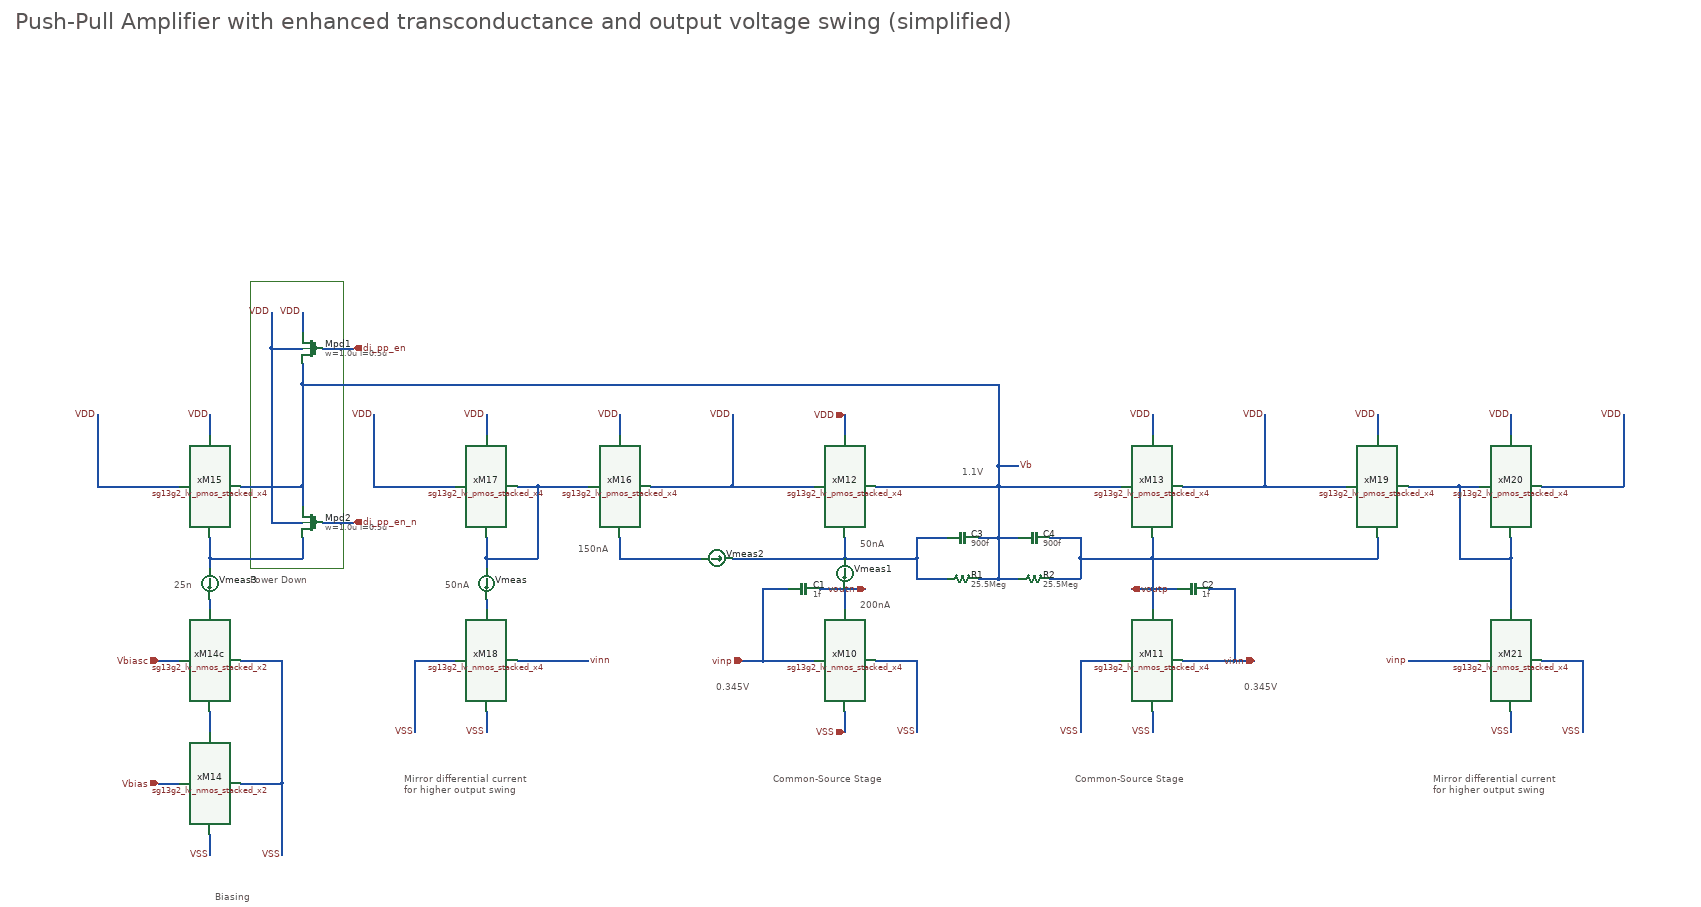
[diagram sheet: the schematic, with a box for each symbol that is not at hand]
v {xschem version=3.4.6 file_version=1.2}
G {}
K {}
V {}
S {}
E {}
P 4 5 640 -1280 640 -1840 820 -1840 820 -1280 640 -1280 {dash = 8}
T {Push-Pull Amplifier with enhanced transconductance and output voltage swing (simplified)} 180 -2360 0 0 1.3 1.3 {}
T {200nA} 1830 -1220 0 0 0.4 0.4 {}
T {Common-Source Stage} 1660 -880 0 0 0.5 0.5 {}
T {Common-Source Stage} 2250 -880 0 0 0.5 0.5 {}
T {Mirror differential current
for higher output swing} 940 -880 0 0 0.5 0.5 {}
T {Mirror differential current
for higher output swing} 2950 -880 0 0 0.5 0.5 {}
T {50nA} 1020 -1260 0 0 0.4 0.4 {}
T {150nA} 1280 -1330 0 0 0.4 0.4 {}
T {50nA} 1830 -1340 0 0 0.4 0.4 {}
T {25n} 490 -1260 0 0 0.4 0.4 {}
T {0.345V} 1550 -1060 0 0 0.4 0.4 {}
T {0.345V} 2580 -1060 0 0 0.4 0.4 {}
T {1.1V} 2030 -1480 0 0 0.4 0.4 {}
T {Power Down} 640 -1270 0 0 0.4 0.4 {}
T {Biasing} 570 -650 0 0 0.5 0.5 {}
N 1800 -1580 1800 -1540 {lab=VDD}
N 1940 -1100 1940 -960 {lab=VSS}
N 2560 -1100 2600 -1100 {lab=vinn}
N 2460 -1100 2560 -1100 {lab=vinn}
N 2260 -1100 2260 -960 {lab=VSS}
N 2400 -1240 2400 -1200 {lab=voutp}
N 1580 -1580 1580 -1440 {lab=VDD}
N 2620 -1580 2620 -1440 {lab=VDD}
N 1580 -1440 1740 -1440 {lab=VDD}
N 2460 -1440 2620 -1440 {lab=VDD}
N 1940 -1260 2000 -1260 {lab=#net1}
N 2200 -1260 2260 -1260 {lab=voutp}
N 2100 -1260 2140 -1260 {lab=Vb}
N 2060 -1260 2100 -1260 {lab=Vb}
N 2100 -1340 2100 -1260 {lab=Vb}
N 2200 -1340 2260 -1340 {lab=voutp}
N 2100 -1340 2140 -1340 {lab=Vb}
N 2060 -1340 2100 -1340 {lab=Vb}
N 1940 -1340 2000 -1340 {lab=#net1}
N 1860 -1440 2100 -1440 {lab=Vb}
N 2100 -1440 2340 -1440 {lab=Vb}
N 2400 -1300 2400 -1240 {lab=voutp}
N 340 -1580 340 -1440 {lab=VDD}
N 340 -1440 500 -1440 {lab=VDD}
N 560 -1580 560 -1540 {lab=VDD}
N 1940 -1300 1940 -1260 {lab=#net1}
N 1420 -1440 1580 -1440 {lab=VDD}
N 2400 -1340 2400 -1300 {lab=voutp}
N 1360 -1580 1360 -1540 {lab=VDD}
N 880 -1440 1040 -1440 {lab=VDD}
N 880 -1580 880 -1440 {lab=VDD}
N 1100 -1580 1100 -1540 {lab=VDD}
N 1160 -1100 1300 -1100 {lab=vinn}
N 1100 -1000 1100 -960 {lab=VSS}
N 1860 -1100 1940 -1100 {lab=VSS}
N 1800 -1000 1800 -960 {lab=VSS}
N 1640 -1100 1740 -1100 {lab=vinp}
N 2400 -1000 2400 -960 {lab=VSS}
N 2260 -1100 2340 -1100 {lab=VSS}
N 2560 -1240 2560 -1100 {lab=vinn}
N 2260 -1300 2260 -1260 {lab=voutp}
N 1360 -1340 1360 -1300 {lab=#net2}
N 1800 -1340 1800 -1300 {lab=#net1}
N 2510 -1240 2560 -1240 {lab=vinn}
N 2400 -1240 2450 -1240 {lab=voutp}
N 1750 -1240 1800 -1240 {lab=voutn}
N 1640 -1240 1690 -1240 {lab=vinp}
N 1640 -1240 1640 -1100 {lab=vinp}
N 1600 -1100 1640 -1100 {lab=vinp}
N 1800 -1240 1800 -1200 {lab=voutn}
N 1200 -1440 1300 -1440 {lab=#net3}
N 1100 -1300 1200 -1300 {lab=#net3}
N 1100 -1340 1100 -1300 {lab=#net3}
N 1200 -1440 1200 -1300 {lab=#net3}
N 1160 -1440 1200 -1440 {lab=#net3}
N 2840 -1580 2840 -1540 {lab=VDD}
N 3160 -1440 3320 -1440 {lab=VDD}
N 3320 -1580 3320 -1440 {lab=VDD}
N 3100 -1580 3100 -1540 {lab=VDD}
N 2900 -1100 3040 -1100 {lab=vinp}
N 3100 -1300 3100 -1200 {lab=#net4}
N 3160 -1100 3240 -1100 {lab=VSS}
N 3240 -1100 3240 -960 {lab=VSS}
N 3100 -1000 3100 -960 {lab=VSS}
N 2840 -1340 2840 -1300 {lab=voutp}
N 2900 -1440 3000 -1440 {lab=#net4}
N 3000 -1300 3100 -1300 {lab=#net4}
N 3100 -1340 3100 -1300 {lab=#net4}
N 3000 -1440 3000 -1300 {lab=#net4}
N 3000 -1440 3040 -1440 {lab=#net4}
N 2620 -1440 2780 -1440 {lab=VDD}
N 1100 -1300 1100 -1280 {lab=#net3}
N 1100 -1220 1100 -1200 {lab=#net5}
N 2400 -1300 2840 -1300 {lab=voutp}
N 2100 -1480 2100 -1440 {lab=Vb}
N 1800 -1300 1940 -1300 {lab=#net1}
N 1940 -1340 1940 -1300 {lab=#net1}
N 2260 -1300 2400 -1300 {lab=voutp}
N 2260 -1340 2260 -1300 {lab=voutp}
N 2100 -1440 2100 -1340 {lab=Vb}
N 2360 -1240 2400 -1240 {lab=voutp}
N 1800 -1240 1840 -1240 {lab=voutn}
N 1360 -1300 1520 -1300 {lab=#net2}
N 1580 -1300 1800 -1300 {lab=#net1}
N 2100 -1480 2140 -1480 {lab=Vb}
N 560 -1300 560 -1280 {lab=#net6}
N 960 -1100 960 -960 {lab=VSS}
N 2400 -1580 2400 -1540 {lab=VDD}
N 2100 -1640 2100 -1480 {lab=Vb}
N 740 -1640 740 -1440 {lab=Vb}
N 740 -1780 740 -1740 {lab=VDD}
N 740 -1440 740 -1400 {lab=Vb}
N 740 -1340 740 -1300 {lab=#net6}
N 560 -1300 740 -1300 {lab=#net6}
N 560 -1340 560 -1300 {lab=#net6}
N 620 -1440 740 -1440 {lab=Vb}
N 740 -1680 740 -1640 {lab=Vb}
N 740 -1640 2100 -1640 {lab=Vb}
N 680 -1710 680 -1370 {lab=VDD}
N 680 -1370 740 -1370 {lab=VDD}
N 680 -1710 740 -1710 {lab=VDD}
N 680 -1780 680 -1710 {lab=VDD}
N 960 -1100 1040 -1100 {lab=VSS}
N 780 -1370 840 -1370 {lab=di_pp_en_n}
N 780 -1710 840 -1710 {lab=di_pp_en}
N 560 -1220 560 -1200 {lab=#net3}
N 620 -1100 700 -1100 {lab=VSS}
N 700 -860 700 -720 {lab=VSS}
N 560 -1000 560 -960 {lab=#net4}
N 560 -760 560 -720 {lab=VSS}
N 620 -860 700 -860 {lab=VSS}
N 700 -1100 700 -860 {lab=VSS}
N 460 -1100 500 -1100 {lab=Vbiasc}
N 460 -860 500 -860 {lab=Vbias}
C {title-2.sym} 0 0 0 0 {name=l2 author="Simon Dorrer" rev=1.0 lock=true}
C {devices/capa.sym} 1720 -1240 1 0 {name=C1
m=1
value=1f
footprint=1206
device="ceramic capacitor"
spice_ignore=True}
C {stacked_transistors/sg13g2_lv_pmos_stacked/sg13g2_lv_pmos_stacked_x4.sym} 1800 -1440 0 1 {name=xM12 W_P=4.0u L_P=40.0u NG_P=8 M_P=1}
C {stacked_transistors/sg13g2_lv_nmos_stacked/sg13g2_lv_nmos_stacked_x4.sym} 1800 -1100 0 0 {name=xM10 W_N=2.0u L_N=40.0u NG_N=4 M_N=1}
C {ipin.sym} 1600 -1100 0 0 {name=p4 lab=vinp}
C {ipin.sym} 2600 -1100 2 0 {name=p6 lab=vinn}
C {opin.sym} 2360 -1240 2 0 {name=p3 lab=voutp}
C {opin.sym} 1840 -1240 2 1 {name=p7 lab=voutn}
C {devices/iopin.sym} 1800 -1580 3 0 {name=p34 lab=VDD}
C {devices/iopin.sym} 1800 -960 1 0 {name=p1 lab=VSS}
C {lab_pin.sym} 1940 -960 3 0 {name=p36 sig_type=std_logic lab=VSS}
C {devices/capa.sym} 2480 -1240 3 1 {name=C2
m=1
value=1f
footprint=1206
device="ceramic capacitor"
spice_ignore=True}
C {lab_pin.sym} 2260 -960 1 1 {name=p12 sig_type=std_logic lab=VSS}
C {res.sym} 2030 -1260 1 1 {name=R1
value=25.5Meg
footprint=1206
device=resistor
m=1}
C {capa.sym} 2030 -1340 1 1 {name=C3
m=1
value=900f
footprint=1206
device="ceramic capacitor"}
C {lab_pin.sym} 2400 -1580 3 1 {name=p5 sig_type=std_logic lab=VDD}
C {lab_pin.sym} 2400 -960 1 1 {name=p8 sig_type=std_logic lab=VSS}
C {stacked_transistors/sg13g2_lv_pmos_stacked/sg13g2_lv_pmos_stacked_x4.sym} 2400 -1440 0 0 {name=xM13 W_P=4.0u L_P=40.0u NG_P=8 M_P=1}
C {stacked_transistors/sg13g2_lv_nmos_stacked/sg13g2_lv_nmos_stacked_x4.sym} 2400 -1100 0 1 {name=xM11 W_N=2.0u L_N=40.0u NG_N=4 M_N=1}
C {capa.sym} 2170 -1340 1 1 {name=C4
m=1
value=900f
footprint=1206
device="ceramic capacitor"}
C {res.sym} 2170 -1260 1 1 {name=R2
value=25.5Meg
footprint=1206
device=resistor
m=1}
C {lab_pin.sym} 2620 -1580 3 1 {name=p9 sig_type=std_logic lab=VDD}
C {lab_pin.sym} 340 -1580 3 1 {name=p13 sig_type=std_logic lab=VDD}
C {lab_pin.sym} 560 -1580 3 1 {name=p14 sig_type=std_logic lab=VDD}
C {stacked_transistors/sg13g2_lv_pmos_stacked/sg13g2_lv_pmos_stacked_x4.sym} 560 -1440 0 1 {name=xM15 W_P=6.0u L_P=40.0u NG_P=12 M_P=1}
C {stacked_transistors/sg13g2_lv_pmos_stacked/sg13g2_lv_pmos_stacked_x4.sym} 1360 -1440 0 0 {name=xM16 W_P=3.0u L_P=40.0u NG_P=6 M_P=1}
C {lab_pin.sym} 1360 -1580 3 1 {name=p15 sig_type=std_logic lab=VDD}
C {lab_pin.sym} 1580 -1580 3 1 {name=p10 sig_type=std_logic lab=VDD}
C {stacked_transistors/sg13g2_lv_pmos_stacked/sg13g2_lv_pmos_stacked_x4.sym} 1100 -1440 0 1 {name=xM17 W_P=1.0u L_P=40.0u NG_P=2 M_P=1}
C {stacked_transistors/sg13g2_lv_nmos_stacked/sg13g2_lv_nmos_stacked_x4.sym} 1100 -1100 0 1 {name=xM18 W_N=0.5u L_N=40.0u NG_N=1 M_N=1}
C {lab_pin.sym} 880 -1580 3 1 {name=p11 sig_type=std_logic lab=VDD}
C {lab_pin.sym} 1100 -1580 3 1 {name=p16 sig_type=std_logic lab=VDD}
C {lab_pin.sym} 1100 -960 3 0 {name=p17 sig_type=std_logic lab=VSS}
C {lab_pin.sym} 1300 -1100 0 1 {name=p19 sig_type=std_logic lab=vinn}
C {stacked_transistors/sg13g2_lv_pmos_stacked/sg13g2_lv_pmos_stacked_x4.sym} 2840 -1440 0 1 {name=xM19 W_P=3.0u L_P=40.0u NG_P=6 M_P=1}
C {lab_pin.sym} 2840 -1580 1 0 {name=p20 sig_type=std_logic lab=VDD}
C {stacked_transistors/sg13g2_lv_pmos_stacked/sg13g2_lv_pmos_stacked_x4.sym} 3100 -1440 0 0 {name=xM20 W_P=1.0u L_P=40.0u NG_P=2 M_P=1}
C {stacked_transistors/sg13g2_lv_nmos_stacked/sg13g2_lv_nmos_stacked_x4.sym} 3100 -1100 0 0 {name=xM21 W_N=0.5u L_N=40.0u NG_N=1 M_N=1}
C {lab_pin.sym} 3320 -1580 1 0 {name=p21 sig_type=std_logic lab=VDD}
C {lab_pin.sym} 3100 -1580 1 0 {name=p22 sig_type=std_logic lab=VDD}
C {lab_pin.sym} 3100 -960 1 1 {name=p23 sig_type=std_logic lab=VSS}
C {lab_pin.sym} 2900 -1100 0 0 {name=p24 sig_type=std_logic lab=vinp}
C {lab_pin.sym} 3240 -960 1 1 {name=p25 sig_type=std_logic lab=VSS}
C {ammeter.sym} 1100 -1250 0 0 {name=Vmeas savecurrent=true spice_ignore=0}
C {ammeter.sym} 1800 -1270 0 0 {name=Vmeas1 savecurrent=true spice_ignore=0}
C {ammeter.sym} 1550 -1300 3 0 {name=Vmeas2 savecurrent=true spice_ignore=0}
C {lab_pin.sym} 2140 -1480 0 1 {name=p26 sig_type=std_logic lab=Vb}
C {lab_pin.sym} 960 -960 1 1 {name=p29 sig_type=std_logic lab=VSS}
C {ammeter.sym} 560 -1250 0 0 {name=Vmeas3 savecurrent=true spice_ignore=0}
C {sg13g2_pr/sg13_hv_pmos.sym} 760 -1370 0 1 {name=Mpd2
l=0.5u
w=1.0u
ng=1
m=1
model=sg13_hv_pmos
spiceprefix=X
}
C {sg13g2_pr/sg13_hv_pmos.sym} 760 -1710 0 1 {name=Mpd1
l=0.5u
w=1.0u
ng=1
m=1
model=sg13_hv_pmos
spiceprefix=X
}
C {lab_pin.sym} 680 -1780 3 1 {name=p2 sig_type=std_logic lab=VDD}
C {lab_pin.sym} 740 -1780 3 1 {name=p18 sig_type=std_logic lab=VDD}
C {ipin.sym} 840 -1710 0 1 {name=p32 lab=di_pp_en}
C {ipin.sym} 840 -1370 0 1 {name=p33 lab=di_pp_en_n}
C {stacked_transistors/sg13g2_lv_nmos_stacked/sg13g2_lv_nmos_stacked_x2.sym} 560 -1100 0 0 {name=xM14c W_N=11.5u L_N=20.0u NG_N=23 M_N=1}
C {lab_pin.sym} 560 -720 1 1 {name=p27 sig_type=std_logic lab=VSS}
C {lab_pin.sym} 700 -720 1 1 {name=p35 sig_type=std_logic lab=VSS}
C {ipin.sym} 460 -860 0 0 {name=p28 lab=Vbias}
C {ipin.sym} 460 -1100 0 0 {name=p30 lab=Vbiasc}
C {stacked_transistors/sg13g2_lv_nmos_stacked/sg13g2_lv_nmos_stacked_x2.sym} 560 -860 0 0 {name=xM14 W_N=11.5u L_N=20.0u NG_N=23 M_N=1}
